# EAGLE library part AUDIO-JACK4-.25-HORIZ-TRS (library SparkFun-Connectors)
1/4" TRS jack, horizontal Production SKU: COM-11144 Footprint unproven - datasheet and part seem to be slightly different

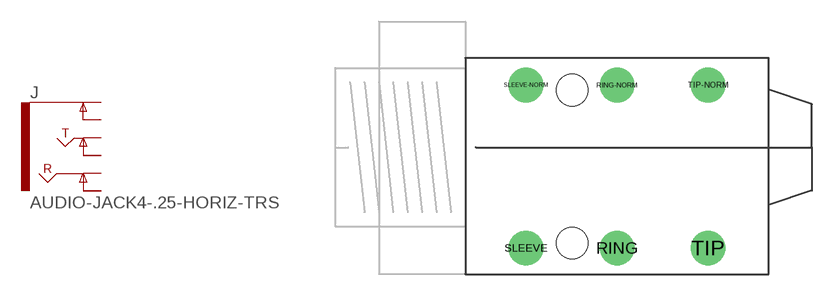
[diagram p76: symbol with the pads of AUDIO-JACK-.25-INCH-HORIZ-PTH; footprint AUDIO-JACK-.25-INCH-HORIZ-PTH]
Designator prefix J

## AUDIO-JACK4-.25-HORIZ-TRS (PROD_ID: CONN-12339; SF_ID: COM-11144)  [AUDIO-JACK-.25-INCH-HORIZ-PTH]
RING  RING
RING-NORM  RING-NORM
SLEEVE  EARTH
SLEEVE-NORM  EARTH-NORM
TIP  TIP
TIP-NORM  TIP-NORM

## Footprint AUDIO-JACK-.25-INCH-HORIZ-PTH (pad centres in mm)
drill 1.6: RING 10.5,-6.95; RING-NORM 10.5,4.35; SLEEVE 4.2,-6.95; SLEEVE-NORM 4.2,4.35; TIP 16.8,-6.95; TIP-NORM 16.8,4.35
hole 2.2 at 7.4,4
hole 2.2 at 7.4,-6.6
